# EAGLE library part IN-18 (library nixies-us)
IN-18: large numeric frontview nixie tube

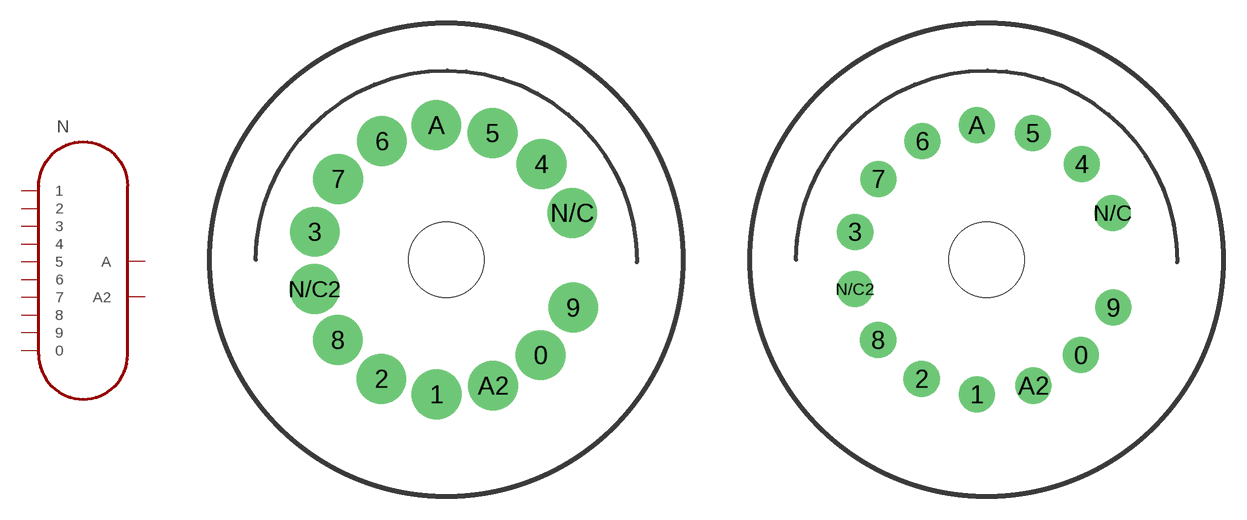
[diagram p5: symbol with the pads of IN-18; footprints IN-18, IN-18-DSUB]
Designator prefix N

## IN-18  [IN-18]
0  0
1  1
2  2
3  3
4  4
5  5
6  6
7  7
8  8
9  9
A  A
A2  A2

## IN-18D-SUB  [IN-18-DSUB]
Pads as for IN-18

## Footprint IN-18 (pad centres in mm)
May be used with socket: PL31-P
drill 2.3 pad 3.2: 0 6.282,-6.357; 1 -0.645,-8.971; 2 -4.33,-7.938; 3 -8.76,1.863; 4 6.35,6.382; 5 3.09,8.449; 6 -4.291,7.907; 7 -7.214,5.386; 8 -7.228,-5.344; 9 8.456,-3.189; A -0.659,8.976; A2 3.123,-8.394; N/C 8.394,3.123; N/C2 -8.781,-1.948
hole 5 at 0,0

## Footprint IN-18-DSUB (pad centres in mm)
May be used with socket: PL31-P
drill 1.6: 0 6.282,-6.357; 1 -0.645,-8.971; 2 -4.33,-7.938; 3 -8.76,1.863; 4 6.35,6.382; 5 3.09,8.449; 6 -4.291,7.907; 7 -7.214,5.386; 8 -7.228,-5.344; 9 8.456,-3.189; A -0.659,8.976; A2 3.123,-8.394; N/C 8.394,3.123; N/C2 -8.781,-1.948
hole 5 at 0,0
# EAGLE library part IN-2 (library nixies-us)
IN-2: tiny numeric topview nixie tube

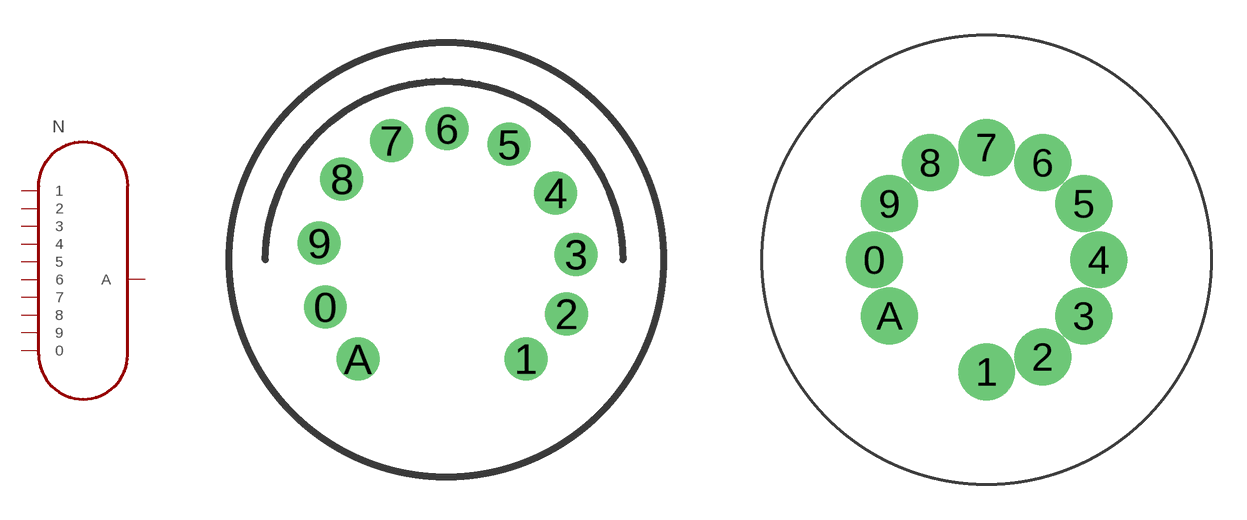
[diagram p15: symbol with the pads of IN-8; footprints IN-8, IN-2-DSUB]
Designator prefix N

## IN-2OLD  [IN-8]
0  0
1  1
2  2
3  3
4  4
5  5
6  6
7  7
8  8
9  9
A  A

## IN-2  [IN-2-DSUB]
Pads as for IN-8

## Footprint IN-8 (pad centres in mm)
May be used with socket: 11-pin- Russian
drill 1: 0 -4.244,-1.655; 1 2.792,-3.483; 2 4.222,-1.907; 3 4.556,0.189; 4 3.837,2.348; 5 2.203,4.052; 6 0.034,4.603; 7 -1.928,4.186; 8 -3.666,2.83; 9 -4.461,0.584; A -3.101,-3.49

## Footprint IN-2-DSUB (pad centres in mm)
drill 1.6 pad 2.184: 0 -4.75,0; 1 0,-4.75; 2 2.375,-4.113; 3 4.113,-2.375; 4 4.75,0; 5 4.113,2.375; 6 2.375,4.113; 7 0,4.75; 8 -2.375,4.113; 9 -4.113,2.375; A -4.113,-2.375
